VERSION 5.7 ;
  NOWIREEXTENSIONATPIN ON ;
  DIVIDERCHAR "/" ;
  BUSBITCHARS "[]" ;
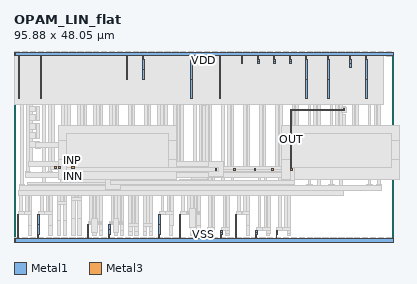
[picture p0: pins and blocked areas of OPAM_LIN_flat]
MACRO OPAM_LIN_flat
  CLASS BLOCK ;
  FOREIGN OPAM_LIN_flat ;
  ORIGIN 1.260 0.000 ;
  SIZE 95.880 BY 48.050 ;
  PIN VSS
    DIRECTION INOUT ;
    USE GROUND ;
    PORT
      LAYER Metal1 ;
        RECT -0.360 4.380 0.000 6.880 ;
        RECT 4.800 4.380 5.160 6.880 ;
        RECT 35.360 4.380 35.720 6.880 ;
        RECT 40.580 4.380 40.940 6.880 ;
        RECT 54.720 4.380 55.080 6.880 ;
        RECT -0.390 1.880 0.000 4.380 ;
        RECT 4.770 1.880 5.160 4.380 ;
        RECT 17.340 3.130 17.700 4.380 ;
        RECT 22.720 3.130 23.080 4.380 ;
        RECT 17.310 1.880 17.700 3.130 ;
        RECT 22.690 1.880 23.080 3.130 ;
        RECT 35.330 1.880 35.720 4.380 ;
        RECT 40.550 1.880 40.940 4.380 ;
        RECT 47.400 2.380 47.760 2.880 ;
        RECT 51.060 2.380 51.420 2.880 ;
        RECT 47.370 1.880 47.760 2.380 ;
        RECT 51.030 1.880 51.420 2.380 ;
        RECT 54.690 1.880 55.080 4.380 ;
        RECT 59.880 2.380 60.240 2.880 ;
        RECT 65.040 2.380 65.400 2.880 ;
        RECT 59.850 1.880 60.240 2.380 ;
        RECT 65.010 1.880 65.400 2.380 ;
        RECT -0.390 0.900 -0.160 1.880 ;
        RECT 4.770 0.900 5.000 1.880 ;
        RECT 17.310 0.900 17.540 1.880 ;
        RECT 22.690 0.900 22.920 1.880 ;
        RECT 35.330 0.900 35.560 1.880 ;
        RECT 40.550 0.900 40.780 1.880 ;
        RECT 47.370 0.900 47.600 1.880 ;
        RECT 51.030 0.900 51.260 1.880 ;
        RECT 54.690 0.900 54.920 1.880 ;
        RECT 59.850 0.900 60.080 1.880 ;
        RECT 65.010 0.900 65.240 1.880 ;
        RECT -1.000 0.000 94.620 0.900 ;
      LAYER Metal3 ;
        RECT -1.260 0.000 94.620 0.900 ;
    END
  END VSS
  PIN VDD
    DIRECTION INOUT ;
    USE POWER ;
    PORT
      LAYER Metal1 ;
        RECT -1.000 47.150 94.620 48.050 ;
        RECT -0.190 46.170 0.040 47.150 ;
        RECT 4.050 47.050 4.530 47.150 ;
        RECT 5.370 46.170 5.600 47.150 ;
        RECT 13.670 47.050 14.150 47.150 ;
        RECT 21.790 47.050 22.270 47.150 ;
        RECT 27.170 46.170 27.400 47.150 ;
        RECT 29.910 47.050 30.390 47.150 ;
        RECT 31.230 46.170 31.460 47.150 ;
        RECT 38.030 47.050 38.510 47.150 ;
        RECT 43.470 46.170 43.700 47.150 ;
        RECT 49.370 47.050 49.850 47.150 ;
        RECT 50.690 46.170 50.920 47.150 ;
        RECT 56.250 46.170 56.480 47.150 ;
        RECT 58.990 47.050 59.470 47.150 ;
        RECT 60.310 46.170 60.540 47.150 ;
        RECT 64.370 46.170 64.600 47.150 ;
        RECT 67.110 47.050 67.590 47.150 ;
        RECT 68.430 46.170 68.660 47.150 ;
        RECT 72.490 46.170 72.720 47.150 ;
        RECT 76.730 47.050 77.210 47.150 ;
        RECT 78.050 46.170 78.280 47.150 ;
        RECT 83.610 46.170 83.840 47.150 ;
        RECT 86.350 47.050 86.830 47.150 ;
        RECT 87.670 46.170 87.900 47.150 ;
        RECT -0.190 41.170 0.200 46.170 ;
        RECT 5.370 41.170 5.760 46.170 ;
        RECT 27.170 43.670 27.560 46.170 ;
        RECT 31.230 43.670 31.620 46.170 ;
        RECT 27.200 41.170 27.560 43.670 ;
        RECT 31.260 41.170 31.620 43.670 ;
        RECT 43.470 41.170 43.860 46.170 ;
        RECT 50.690 41.170 51.080 46.170 ;
        RECT 56.250 45.670 56.640 46.170 ;
        RECT 60.310 45.670 60.700 46.170 ;
        RECT 64.370 45.670 64.760 46.170 ;
        RECT 68.430 45.670 68.820 46.170 ;
        RECT 56.280 45.170 56.640 45.670 ;
        RECT 60.340 45.170 60.700 45.670 ;
        RECT 64.400 45.170 64.760 45.670 ;
        RECT 68.460 45.170 68.820 45.670 ;
        RECT 72.490 41.170 72.880 46.170 ;
        RECT 78.050 41.170 78.440 46.170 ;
        RECT 83.610 45.170 84.000 46.170 ;
        RECT 83.640 44.170 84.000 45.170 ;
        RECT 87.670 41.170 88.060 46.170 ;
        RECT -0.160 36.170 0.200 41.170 ;
        RECT 5.400 36.170 5.760 41.170 ;
        RECT 43.500 36.170 43.860 41.170 ;
        RECT 50.720 36.170 51.080 41.170 ;
        RECT 72.520 36.170 72.880 41.170 ;
        RECT 78.080 36.170 78.440 41.170 ;
        RECT 87.700 36.170 88.060 41.170 ;
      LAYER Metal3 ;
        RECT -1.260 47.150 94.620 48.050 ;
    END
  END VDD
  PIN INN
    DIRECTION INPUT ;
    ANTENNAGATEAREA 9.000000 ;
    PORT
      LAYER Metal3 ;
      RECT 13.520 16.180 13.950 16.720 ;
      RECT 14.640 16.180 15.050 16.720 ;
      RECT 15.750 16.180 16.160 16.720 ;
    END
  END INN
  PIN OUT
    DIRECTION INOUT ;
    ANTENNAGATEAREA 4.000000 ;
    ANTENNADIFFAREA 9.240000 ;
    PORT
      LAYER Metal3 ;
        RECT 81.990 33.590 82.390 33.640 ;
      RECT 68.725 33.290 82.390 33.590 ;
      RECT 68.725 18.560 69.025 33.290 ;
        RECT 81.990 33.240 82.390 33.290 ;
      RECT 49.675 18.160 50.075 18.560 ;
      RECT 54.375 18.000 54.800 18.560 ;
      RECT 59.440 18.000 59.875 18.560 ;
      RECT 63.875 18.000 64.320 18.560 ;
      RECT 68.675 18.160 69.075 18.560 ;
    END
  END OUT
  PIN INP
    DIRECTION INPUT ;
    ANTENNAGATEAREA 8.050000 ;
    PORT
      LAYER Metal3 ;
      RECT 9.040 18.560 9.490 19.220 ;
      RECT 9.990 18.560 10.560 19.220 ;
      RECT 13.290 18.560 13.920 19.220 ;
    END
  END INP
  OBS
      LAYER Via1 ;
        RECT 81.760 24.010 82.620 27.620 ;
        RECT 48.670 1.650 49.490 2.150 ;
        RECT 52.330 1.650 53.150 2.150 ;
        RECT 62.650 1.650 63.470 2.150 ;
        RECT 67.810 1.650 68.630 2.150 ;
        RECT 18.690 1.650 19.510 2.450 ;
        RECT 24.070 1.650 24.890 2.450 ;
        RECT 27.810 1.650 28.630 2.650 ;
        RECT 29.310 1.650 30.130 2.650 ;
        RECT 31.470 1.650 32.290 2.650 ;
        RECT 32.970 1.650 33.790 2.650 ;
        RECT 48.670 2.150 49.520 2.870 ;
        RECT 52.330 2.150 53.180 2.870 ;
        RECT 62.650 2.150 63.500 2.870 ;
        RECT 67.810 2.150 68.660 2.870 ;
        RECT 47.760 2.870 49.520 2.880 ;
        RECT 51.420 2.870 53.180 2.880 ;
        RECT 60.240 2.870 61.540 2.880 ;
        RECT 65.400 2.870 66.700 2.880 ;
        RECT 20.270 1.650 21.090 2.900 ;
        RECT 25.650 1.650 26.470 2.900 ;
        RECT 47.600 2.880 49.520 3.690 ;
        RECT 51.260 2.880 53.180 3.690 ;
        RECT 60.080 2.880 61.540 3.690 ;
        RECT 61.580 2.870 63.500 3.690 ;
        RECT 65.240 2.880 66.700 3.690 ;
        RECT 66.740 2.870 68.660 3.690 ;
        RECT 43.430 1.650 44.250 3.700 ;
        RECT 27.780 2.650 28.630 3.870 ;
        RECT 29.310 2.650 30.160 3.870 ;
        RECT 31.440 2.650 32.290 3.870 ;
        RECT 32.970 2.650 33.820 3.870 ;
        RECT 2.410 1.650 3.230 4.150 ;
        RECT 7.570 1.650 8.390 4.150 ;
        RECT 38.130 1.650 38.950 4.150 ;
        RECT 45.010 1.650 45.830 4.150 ;
        RECT 57.490 1.650 58.310 4.150 ;
        RECT 18.420 2.450 19.780 4.370 ;
        RECT 20.270 2.900 21.120 4.370 ;
        RECT 23.800 2.450 25.160 4.370 ;
        RECT 25.650 2.900 26.500 4.370 ;
        RECT 17.700 4.370 21.120 4.380 ;
        RECT 23.080 4.370 26.500 4.380 ;
        RECT 27.780 3.870 30.160 4.690 ;
        RECT 31.440 3.870 33.820 4.690 ;
        RECT 17.540 4.380 21.120 5.190 ;
        RECT 22.920 4.380 26.500 5.190 ;
        RECT 9.730 1.650 10.550 5.400 ;
        RECT 11.230 1.650 12.050 5.400 ;
        RECT 13.390 1.650 14.210 5.900 ;
        RECT 14.890 1.650 15.710 5.900 ;
        RECT 17.925 5.190 20.275 6.040 ;
        RECT 23.305 5.190 25.655 6.040 ;
        RECT 2.410 4.150 3.260 6.870 ;
        RECT 7.570 4.150 8.420 6.870 ;
        RECT 38.130 4.150 38.980 6.870 ;
        RECT 43.160 3.700 44.520 6.870 ;
        RECT 45.010 4.150 45.860 6.870 ;
        RECT 57.490 4.150 58.340 6.870 ;
        RECT 0.000 6.870 1.300 6.880 ;
        RECT 5.160 6.870 6.460 6.880 ;
        RECT 35.720 6.870 37.020 6.880 ;
        RECT 40.940 6.870 42.240 6.880 ;
        RECT 55.080 6.870 56.380 6.880 ;
        RECT -0.160 6.880 1.300 7.690 ;
        RECT 1.340 6.870 3.260 7.690 ;
        RECT 5.000 6.880 6.460 7.690 ;
        RECT 6.500 6.870 8.420 7.690 ;
        RECT 35.560 6.880 37.020 7.690 ;
        RECT 37.060 6.870 38.980 7.690 ;
        RECT 40.780 6.880 42.240 7.690 ;
        RECT 42.280 6.870 45.860 7.690 ;
        RECT 54.920 6.880 56.380 7.690 ;
        RECT 56.420 6.870 58.340 7.690 ;
        RECT 42.665 7.690 45.015 8.540 ;
        RECT 9.700 5.400 10.550 9.370 ;
        RECT 11.230 5.400 12.080 9.370 ;
        RECT 9.700 9.370 12.080 10.190 ;
        RECT 13.360 5.900 14.210 10.370 ;
        RECT 14.890 5.900 15.740 10.370 ;
        RECT 13.360 10.370 15.740 11.190 ;
        RECT 0.225 7.690 0.915 11.740 ;
        RECT 5.385 7.690 6.075 11.740 ;
        RECT 35.945 7.690 36.635 11.740 ;
        RECT 55.305 7.690 55.995 11.740 ;
        RECT 56.805 7.690 57.495 11.740 ;
        RECT 57.650 7.690 58.340 11.740 ;
        RECT -0.110 11.740 1.250 11.790 ;
        RECT 1.725 7.690 2.415 11.790 ;
        RECT 2.570 7.690 3.260 11.790 ;
        RECT 5.050 11.740 6.410 11.790 ;
        RECT 6.885 7.690 7.575 11.790 ;
        RECT 7.730 7.690 8.420 11.790 ;
        RECT 9.700 10.190 10.390 11.790 ;
        RECT 10.545 10.190 11.235 11.790 ;
        RECT 11.390 10.190 12.080 11.790 ;
        RECT 13.360 11.190 14.050 11.790 ;
        RECT 14.205 11.190 14.895 11.790 ;
        RECT 15.050 11.190 15.740 11.790 ;
        RECT 17.925 6.040 18.615 11.790 ;
        RECT 18.755 6.040 19.445 11.790 ;
        RECT 19.585 6.040 20.275 11.790 ;
        RECT 20.430 5.190 21.120 11.790 ;
        RECT 23.305 6.040 23.995 11.790 ;
        RECT 24.135 6.040 24.825 11.790 ;
        RECT 24.965 6.040 25.655 11.790 ;
        RECT 25.810 5.190 26.500 11.790 ;
        RECT 27.780 4.690 28.470 11.790 ;
        RECT 28.625 4.690 29.315 11.790 ;
        RECT 29.470 4.690 30.160 11.790 ;
        RECT 31.440 4.690 32.130 11.790 ;
        RECT 32.285 4.690 32.975 11.790 ;
        RECT 33.130 4.690 33.820 11.790 ;
        RECT 35.610 11.740 36.970 11.790 ;
        RECT 37.445 7.690 38.135 11.790 ;
        RECT 38.290 7.690 38.980 11.790 ;
        RECT 41.165 7.690 41.855 11.790 ;
        RECT 42.665 8.540 43.355 11.790 ;
        RECT 43.495 8.540 44.185 11.790 ;
        RECT 44.325 8.540 45.015 11.790 ;
        RECT 45.170 7.690 45.860 11.790 ;
        RECT 47.985 3.690 48.675 11.790 ;
        RECT 48.830 3.690 49.520 11.790 ;
        RECT 51.645 3.690 52.335 11.790 ;
        RECT 52.490 3.690 53.180 11.790 ;
        RECT 54.970 11.740 56.330 11.790 ;
        RECT 56.805 11.740 58.675 11.790 ;
        RECT 60.465 3.690 61.155 11.790 ;
        RECT 61.965 3.690 62.655 11.790 ;
        RECT 62.810 3.690 63.500 11.790 ;
        RECT 65.625 3.690 66.315 11.790 ;
        RECT 67.125 3.690 67.815 11.790 ;
        RECT 67.970 3.690 68.660 11.790 ;
        RECT 80.675 11.740 82.035 11.790 ;
        RECT -0.110 11.790 82.035 13.050 ;
        RECT -0.110 13.050 1.250 13.060 ;
        RECT 1.390 13.050 76.475 13.060 ;
        RECT -0.110 13.060 76.475 13.100 ;
        RECT 80.675 13.050 82.035 13.100 ;
        RECT 0.090 13.100 76.475 13.110 ;
        RECT 78.330 13.060 79.690 13.110 ;
        RECT 81.010 13.100 81.700 13.110 ;
        RECT 87.950 13.060 89.310 13.110 ;
        RECT 90.295 13.060 91.655 13.110 ;
        RECT 0.090 13.110 91.655 14.370 ;
        RECT 23.045 14.370 24.825 14.380 ;
        RECT 0.090 14.370 1.450 14.420 ;
        RECT 61.965 14.370 63.835 14.420 ;
        RECT 72.770 14.370 74.130 14.420 ;
        RECT 78.330 14.370 79.690 14.420 ;
        RECT 87.950 14.370 89.310 14.420 ;
        RECT 90.295 14.370 91.655 14.420 ;
        RECT 2.235 14.370 14.895 14.430 ;
        RECT 15.050 14.370 15.740 14.430 ;
        RECT 15.960 14.370 19.940 14.430 ;
        RECT 20.430 14.370 21.120 14.430 ;
        RECT 23.045 14.380 25.160 14.430 ;
        RECT 2.235 14.430 25.160 15.030 ;
        RECT 27.780 14.370 54.675 15.030 ;
        RECT 40.685 15.030 46.195 15.040 ;
        RECT 2.235 15.030 3.595 15.080 ;
        RECT 7.395 15.030 8.755 15.080 ;
        RECT 9.365 15.030 11.235 15.080 ;
        RECT 53.315 15.030 54.675 15.080 ;
        RECT 31.440 15.030 33.820 15.080 ;
        RECT 40.685 15.040 47.440 15.080 ;
        RECT 11.390 15.030 25.160 15.090 ;
        RECT 25.810 14.370 26.500 15.090 ;
        RECT 27.780 15.030 30.160 15.090 ;
        RECT 40.685 15.080 45.110 15.090 ;
        RECT 46.080 15.080 47.440 15.090 ;
        RECT 40.685 15.090 47.585 15.690 ;
        RECT 40.830 15.690 42.190 15.740 ;
        RECT 43.160 15.690 47.585 15.740 ;
        RECT 11.390 15.090 30.160 15.740 ;
        RECT 11.390 15.740 12.080 15.750 ;
        RECT 12.390 15.740 30.160 15.750 ;
        RECT 31.440 15.080 32.130 15.750 ;
        RECT 33.130 15.080 33.820 15.750 ;
        RECT 36.415 15.700 37.775 15.750 ;
        RECT 43.605 15.740 47.585 16.350 ;
        RECT 46.080 16.350 47.440 16.360 ;
        RECT 53.650 15.080 54.340 16.360 ;
        RECT 60.465 14.370 61.155 16.360 ;
        RECT 61.965 14.420 62.655 16.360 ;
        RECT 65.625 14.370 66.315 16.360 ;
        RECT 67.125 14.370 67.815 16.360 ;
        RECT 67.970 14.370 68.660 16.360 ;
        RECT 75.450 14.370 76.140 16.360 ;
        RECT 81.010 14.370 81.700 16.360 ;
        RECT 90.630 14.420 91.320 16.360 ;
        RECT 43.750 16.350 45.110 16.400 ;
        RECT 45.250 16.360 47.440 16.400 ;
        RECT 1.590 16.360 2.950 16.410 ;
        RECT 5.985 15.030 6.675 16.410 ;
        RECT 7.150 16.360 8.510 16.410 ;
        RECT 10.545 15.080 11.235 16.410 ;
        RECT 11.390 15.750 37.775 16.410 ;
        RECT 38.290 15.030 38.980 16.410 ;
        RECT 44.085 16.400 44.775 16.410 ;
        RECT 45.250 16.400 47.105 16.410 ;
        RECT 47.985 15.030 48.675 16.410 ;
        RECT 48.830 15.030 49.520 16.410 ;
        RECT 51.305 15.030 51.995 16.410 ;
        RECT 52.470 16.360 54.340 16.410 ;
        RECT 60.130 16.360 61.490 16.410 ;
        RECT 61.630 16.360 62.990 16.410 ;
        RECT 65.290 16.360 66.650 16.410 ;
        RECT 66.790 16.360 68.995 16.410 ;
        RECT 73.105 14.420 73.795 16.410 ;
        RECT 74.270 16.360 76.140 16.410 ;
        RECT 78.665 14.420 79.355 16.410 ;
        RECT 79.830 16.360 81.700 16.410 ;
        RECT 83.890 16.360 86.095 16.410 ;
        RECT 88.285 14.420 88.975 16.410 ;
        RECT 89.450 16.360 91.320 16.410 ;
        RECT 1.590 16.410 91.320 17.670 ;
        RECT 10.545 17.670 11.235 17.680 ;
        RECT 11.390 17.670 13.125 17.680 ;
        RECT 23.390 17.670 70.070 17.680 ;
        RECT 1.590 17.670 2.950 17.720 ;
        RECT 7.150 17.670 8.510 17.720 ;
        RECT 18.820 17.670 20.690 17.720 ;
        RECT 74.270 17.670 76.140 17.720 ;
        RECT 79.830 17.670 81.700 17.720 ;
        RECT 83.890 17.670 86.095 17.720 ;
        RECT 89.450 17.670 91.320 17.720 ;
        RECT 10.545 17.680 13.125 17.730 ;
        RECT 15.605 17.670 16.295 17.730 ;
        RECT 16.450 17.670 17.140 17.730 ;
        RECT 18.820 17.720 19.510 17.730 ;
        RECT 19.665 17.720 20.355 17.730 ;
        RECT 22.545 17.680 70.915 17.730 ;
        RECT 10.545 17.730 70.915 18.330 ;
        RECT 47.985 18.330 70.915 18.340 ;
        RECT 8.600 18.330 34.155 18.380 ;
        RECT 38.290 18.330 40.145 18.380 ;
        RECT 7.485 17.720 8.175 18.390 ;
        RECT 8.600 18.380 33.715 18.390 ;
        RECT 36.750 18.330 37.440 18.390 ;
        RECT 38.290 18.380 38.980 18.390 ;
        RECT 39.120 18.380 39.810 18.390 ;
        RECT 40.475 18.340 41.835 18.390 ;
        RECT 44.085 18.330 44.775 18.390 ;
        RECT 45.585 18.330 46.275 18.390 ;
        RECT 46.415 18.330 47.105 18.390 ;
        RECT 47.650 18.340 70.915 18.390 ;
        RECT 7.485 18.390 70.915 18.990 ;
        RECT 1.925 17.720 2.615 19.000 ;
        RECT 7.485 18.990 14.880 19.000 ;
        RECT 15.605 18.990 16.295 19.000 ;
        RECT 19.665 18.990 20.355 19.000 ;
        RECT 22.545 18.990 24.415 19.040 ;
        RECT 56.865 18.990 58.735 19.040 ;
        RECT 60.925 18.990 62.795 19.040 ;
        RECT 64.985 18.990 66.855 19.040 ;
        RECT 68.185 18.990 70.915 19.040 ;
        RECT 25.475 18.990 50.565 19.040 ;
        RECT 1.925 19.000 3.795 19.050 ;
        RECT 5.985 17.670 6.675 19.050 ;
        RECT 7.485 19.000 16.295 19.050 ;
        RECT 19.665 19.000 21.535 19.050 ;
        RECT 22.880 19.040 23.570 19.050 ;
        RECT 23.725 19.040 24.415 19.050 ;
        RECT 24.570 18.990 25.260 19.050 ;
        RECT 25.475 19.040 49.115 19.050 ;
        RECT 49.185 19.040 50.565 19.050 ;
        RECT 53.650 18.990 55.265 19.050 ;
        RECT 58.985 18.990 60.365 19.050 ;
        RECT 63.385 18.990 64.765 19.050 ;
        RECT 68.185 19.040 69.735 19.050 ;
        RECT 1.925 19.050 16.295 20.310 ;
        RECT 19.665 19.050 49.115 20.310 ;
        RECT 1.925 20.310 3.795 20.360 ;
        RECT 7.485 20.310 9.355 20.360 ;
        RECT 10.365 20.310 12.235 20.360 ;
        RECT 14.425 20.310 16.295 20.360 ;
        RECT 19.665 20.310 21.535 20.360 ;
        RECT 27.450 20.310 30.495 20.360 ;
        RECT 31.510 20.310 33.380 20.360 ;
        RECT 34.725 20.310 37.440 20.360 ;
        RECT 37.955 20.310 41.500 20.360 ;
        RECT 46.415 20.310 49.115 20.360 ;
        RECT 2.770 20.360 3.460 24.010 ;
        RECT 4.130 23.750 5.510 24.010 ;
        RECT 2.770 24.010 5.510 25.130 ;
        RECT 2.770 25.130 4.160 25.370 ;
        RECT 4.390 25.130 5.250 25.370 ;
        RECT 2.770 25.370 3.460 26.260 ;
        RECT 2.770 26.260 4.160 27.620 ;
        RECT 2.770 27.620 3.460 28.510 ;
        RECT 2.770 28.510 4.160 29.870 ;
        RECT 2.770 29.870 3.460 30.760 ;
        RECT 2.770 30.760 4.160 32.120 ;
        RECT 81.010 17.720 81.700 32.750 ;
        RECT 2.770 32.120 3.460 33.010 ;
        RECT 81.010 32.750 82.880 34.130 ;
        RECT 2.770 33.010 4.160 34.370 ;
        RECT 81.760 34.130 82.620 34.370 ;
        RECT 45.585 20.310 46.275 34.510 ;
        RECT 46.415 20.360 47.105 34.510 ;
        RECT 47.245 20.360 47.935 34.510 ;
        RECT 0.425 14.420 1.115 35.360 ;
        RECT 1.925 20.360 2.615 35.360 ;
        RECT 2.770 34.370 3.460 35.360 ;
        RECT 5.985 20.310 6.675 35.360 ;
        RECT 7.485 20.360 8.175 35.360 ;
        RECT 8.330 20.360 9.020 35.360 ;
        RECT 18.820 18.990 19.510 35.360 ;
        RECT 19.665 20.360 20.355 35.360 ;
        RECT 20.510 20.360 21.200 35.360 ;
        RECT 22.880 20.310 23.570 35.360 ;
        RECT 23.725 20.310 24.415 35.360 ;
        RECT 24.570 20.310 25.260 35.360 ;
        RECT 44.085 20.310 44.775 35.360 ;
        RECT 45.585 34.510 47.935 35.360 ;
        RECT 48.090 20.360 48.780 35.360 ;
        RECT 51.305 18.990 51.995 35.360 ;
        RECT 52.805 18.990 53.495 35.360 ;
        RECT 53.650 19.050 54.340 35.360 ;
        RECT 73.105 17.670 73.795 35.360 ;
        RECT 74.605 17.720 75.295 35.360 ;
        RECT 75.450 17.720 76.140 35.360 ;
        RECT 78.665 17.670 79.355 35.360 ;
        RECT 80.165 17.720 80.855 35.360 ;
        RECT 81.010 34.130 81.700 35.360 ;
        RECT 88.285 17.670 88.975 35.360 ;
        RECT 89.785 17.720 90.475 35.360 ;
        RECT 90.630 17.720 91.320 35.360 ;
        RECT 0.040 35.360 1.500 36.170 ;
        RECT 5.600 35.360 7.060 36.170 ;
        RECT 43.700 35.360 45.160 36.170 ;
        RECT 50.920 35.360 52.380 36.170 ;
        RECT 72.720 35.360 74.180 36.170 ;
        RECT 78.280 35.360 79.740 36.170 ;
        RECT 87.900 35.360 89.360 36.170 ;
        RECT 0.200 36.170 1.500 36.180 ;
        RECT 1.540 35.360 3.460 36.180 ;
        RECT 5.760 36.170 7.060 36.180 ;
        RECT 7.100 35.360 9.020 36.180 ;
        RECT 43.860 36.170 45.160 36.180 ;
        RECT 45.200 35.360 48.780 36.180 ;
        RECT 51.080 36.170 52.380 36.180 ;
        RECT 52.420 35.360 54.340 36.180 ;
        RECT 72.880 36.170 74.180 36.180 ;
        RECT 74.220 35.360 76.140 36.180 ;
        RECT 78.440 36.170 79.740 36.180 ;
        RECT 79.780 35.360 81.700 36.180 ;
        RECT 88.060 36.170 89.360 36.180 ;
        RECT 89.400 35.360 91.320 36.180 ;
        RECT 18.820 35.360 21.200 36.180 ;
        RECT 22.880 35.360 25.260 36.180 ;
        RECT 27.785 20.360 28.475 40.360 ;
        RECT 28.630 20.360 29.320 40.360 ;
        RECT 31.845 20.360 32.535 40.360 ;
        RECT 32.690 20.360 33.380 40.360 ;
        RECT 27.400 40.360 29.320 41.170 ;
        RECT 31.460 40.360 33.380 41.170 ;
        RECT 27.560 41.170 29.320 41.180 ;
        RECT 31.620 41.170 33.380 41.180 ;
        RECT 35.060 20.360 35.750 41.360 ;
        RECT 35.905 20.360 36.595 41.360 ;
        RECT 36.750 20.360 37.440 41.360 ;
        RECT 39.120 20.360 39.810 41.360 ;
        RECT 39.965 20.360 40.655 41.360 ;
        RECT 40.810 20.360 41.500 41.360 ;
        RECT 2.610 36.180 3.460 41.400 ;
        RECT 8.170 36.180 9.020 41.400 ;
        RECT 18.820 36.180 19.670 41.400 ;
        RECT 20.350 36.180 21.200 41.400 ;
        RECT 22.880 36.180 23.730 41.400 ;
        RECT 24.410 36.180 25.260 41.400 ;
        RECT 47.930 36.180 48.780 41.400 ;
        RECT 53.490 36.180 54.340 41.400 ;
        RECT 75.290 36.180 76.140 41.400 ;
        RECT 80.850 36.180 81.700 41.400 ;
        RECT 90.470 36.180 91.320 41.400 ;
        RECT 46.080 36.180 47.440 41.850 ;
        RECT 35.060 41.360 37.440 42.180 ;
        RECT 39.120 41.360 41.500 42.180 ;
        RECT 84.225 17.720 84.915 43.360 ;
        RECT 85.070 17.720 85.760 43.360 ;
        RECT 28.470 41.180 29.320 43.900 ;
        RECT 32.530 41.180 33.380 43.900 ;
        RECT 83.840 43.360 85.760 44.170 ;
        RECT 84.000 44.170 85.760 44.180 ;
        RECT 56.865 19.040 57.555 44.360 ;
        RECT 57.710 19.040 58.400 44.360 ;
        RECT 60.925 19.040 61.615 44.360 ;
        RECT 61.770 19.040 62.460 44.360 ;
        RECT 64.985 19.040 65.675 44.360 ;
        RECT 65.830 19.040 66.520 44.360 ;
        RECT 69.045 19.050 69.735 44.360 ;
        RECT 69.890 19.040 70.580 44.360 ;
        RECT 35.060 42.180 35.910 44.400 ;
        RECT 36.590 42.180 37.440 44.400 ;
        RECT 39.120 42.180 39.970 44.400 ;
        RECT 40.650 42.180 41.500 44.400 ;
        RECT 10.700 20.360 11.390 44.810 ;
        RECT 11.545 20.360 12.235 44.810 ;
        RECT 12.390 20.310 13.080 44.810 ;
        RECT 14.760 20.360 15.450 44.860 ;
        RECT 15.605 20.360 16.295 44.860 ;
        RECT 16.450 18.990 17.140 44.860 ;
        RECT 56.480 44.360 58.400 45.170 ;
        RECT 60.540 44.360 62.460 45.170 ;
        RECT 64.600 44.360 66.520 45.170 ;
        RECT 68.660 44.360 70.580 45.170 ;
        RECT 56.640 45.170 58.400 45.180 ;
        RECT 60.700 45.170 62.460 45.180 ;
        RECT 64.760 45.170 66.520 45.180 ;
        RECT 68.820 45.170 70.580 45.180 ;
        RECT 84.910 44.180 85.760 45.400 ;
        RECT 10.700 44.810 13.080 45.630 ;
        RECT 14.760 44.860 17.140 45.680 ;
        RECT 57.550 45.180 58.400 45.900 ;
        RECT 61.610 45.180 62.460 45.900 ;
        RECT 65.670 45.180 66.520 45.900 ;
        RECT 69.730 45.180 70.580 45.900 ;
        RECT 10.700 45.630 11.550 46.125 ;
        RECT 12.230 45.630 13.080 46.125 ;
        RECT 14.760 45.680 15.610 46.150 ;
        RECT 16.290 45.680 17.140 46.150 ;
        RECT 2.610 41.400 3.430 46.400 ;
        RECT 8.170 41.400 8.990 46.400 ;
        RECT 10.730 46.125 11.550 46.400 ;
        RECT 12.230 46.125 13.050 46.400 ;
        RECT 14.790 46.150 15.610 46.400 ;
        RECT 16.290 46.150 17.110 46.400 ;
        RECT 18.850 41.400 19.670 46.400 ;
        RECT 20.350 41.400 21.170 46.400 ;
        RECT 22.910 41.400 23.730 46.400 ;
        RECT 24.410 41.400 25.230 46.400 ;
        RECT 28.470 43.900 29.290 46.400 ;
        RECT 32.530 43.900 33.350 46.400 ;
        RECT 35.090 44.400 35.910 46.400 ;
        RECT 36.590 44.400 37.410 46.400 ;
        RECT 39.150 44.400 39.970 46.400 ;
        RECT 40.650 44.400 41.470 46.400 ;
        RECT 46.350 41.850 47.170 46.400 ;
        RECT 47.930 41.400 48.750 46.400 ;
        RECT 53.490 41.400 54.310 46.400 ;
        RECT 57.550 45.900 58.370 46.400 ;
        RECT 61.610 45.900 62.430 46.400 ;
        RECT 65.670 45.900 66.490 46.400 ;
        RECT 69.730 45.900 70.550 46.400 ;
        RECT 75.290 41.400 76.110 46.400 ;
        RECT 80.850 41.400 81.670 46.400 ;
        RECT 84.910 45.400 85.730 46.400 ;
        RECT 90.470 41.400 91.290 46.400 ;
        RECT 81.760 28.510 82.620 32.120 ;
        RECT 46.850 46.910 48.230 48.290 ;
        RECT 48.850 46.910 50.230 48.290 ;
        RECT 50.850 46.910 52.230 48.290 ;
        RECT 52.850 46.910 54.230 48.290 ;
        RECT 54.850 46.910 56.230 48.290 ;
        RECT 56.850 46.910 58.230 48.290 ;
        RECT 58.850 46.910 60.230 48.290 ;
        RECT 60.850 46.910 62.230 48.290 ;
        RECT 62.850 46.910 64.230 48.290 ;
        RECT 64.850 46.910 66.230 48.290 ;
        RECT 66.850 46.910 68.230 48.290 ;
        RECT 68.850 46.910 70.230 48.290 ;
        RECT 70.850 46.910 72.230 48.290 ;
        RECT 72.850 46.910 74.230 48.290 ;
        RECT 74.850 46.910 76.230 48.290 ;
        RECT 76.850 46.910 78.230 48.290 ;
        RECT 78.850 46.910 80.230 48.290 ;
        RECT 80.850 46.910 82.230 48.290 ;
        RECT 82.850 46.910 84.230 48.290 ;
        RECT 84.850 46.910 86.230 48.290 ;
        RECT 86.850 46.910 88.230 48.290 ;
        RECT 88.850 46.910 90.230 48.290 ;
        RECT 90.850 46.910 92.230 48.290 ;
        RECT 92.850 46.910 94.230 48.290 ;
        RECT 42.850 46.910 44.230 48.290 ;
        RECT 44.850 46.910 46.230 48.290 ;
        RECT 4.390 30.760 5.250 34.370 ;
        RECT 4.390 26.260 5.250 29.870 ;
        RECT -1.150 46.910 0.230 48.290 ;
        RECT 0.850 46.910 2.230 48.290 ;
        RECT 2.850 46.910 4.230 48.290 ;
        RECT 4.850 46.910 6.230 48.290 ;
        RECT 6.850 46.910 8.230 48.290 ;
        RECT 8.850 46.910 10.230 48.290 ;
        RECT 10.850 46.910 12.230 48.290 ;
        RECT 12.850 46.910 14.230 48.290 ;
        RECT 14.850 46.910 16.230 48.290 ;
        RECT 16.850 46.910 18.230 48.290 ;
        RECT 18.850 46.910 20.230 48.290 ;
        RECT 20.850 46.910 22.230 48.290 ;
        RECT 22.850 46.910 24.230 48.290 ;
        RECT 24.850 46.910 26.230 48.290 ;
        RECT 26.850 46.910 28.230 48.290 ;
        RECT 28.850 46.910 30.230 48.290 ;
        RECT 30.850 46.910 32.230 48.290 ;
        RECT 32.850 46.910 34.230 48.290 ;
        RECT 34.850 46.910 36.230 48.290 ;
        RECT 36.850 46.910 38.230 48.290 ;
        RECT 38.850 46.910 40.230 48.290 ;
        RECT 40.850 46.910 42.230 48.290 ;
        RECT 8.850 -0.240 10.230 1.140 ;
        RECT 10.850 -0.240 12.230 1.140 ;
        RECT 12.850 -0.240 14.230 1.140 ;
        RECT 14.850 -0.240 16.230 1.140 ;
        RECT 16.850 -0.240 18.230 1.140 ;
        RECT 18.850 -0.240 20.230 1.140 ;
        RECT 20.850 -0.240 22.230 1.140 ;
        RECT 22.850 -0.240 24.230 1.140 ;
        RECT 24.850 -0.240 26.230 1.140 ;
        RECT 26.850 -0.240 28.230 1.140 ;
        RECT 28.850 -0.240 30.230 1.140 ;
        RECT 30.850 -0.240 32.230 1.140 ;
        RECT 32.850 -0.240 34.230 1.140 ;
        RECT 34.850 -0.240 36.230 1.140 ;
        RECT 36.850 -0.240 38.230 1.140 ;
        RECT 38.850 -0.240 40.230 1.140 ;
        RECT 40.850 -0.240 42.230 1.140 ;
        RECT 42.850 -0.240 44.230 1.140 ;
        RECT 44.850 -0.240 46.230 1.140 ;
        RECT -1.150 -0.240 0.230 1.140 ;
        RECT 0.850 -0.240 2.230 1.140 ;
        RECT 2.850 -0.240 4.230 1.140 ;
        RECT 4.850 -0.240 6.230 1.140 ;
        RECT 6.850 -0.240 8.230 1.140 ;
        RECT 56.850 -0.240 58.230 1.140 ;
        RECT 58.850 -0.240 60.230 1.140 ;
        RECT 60.850 -0.240 62.230 1.140 ;
        RECT 62.850 -0.240 64.230 1.140 ;
        RECT 64.850 -0.240 66.230 1.140 ;
        RECT 66.850 -0.240 68.230 1.140 ;
        RECT 68.850 -0.240 70.230 1.140 ;
        RECT 70.850 -0.240 72.230 1.140 ;
        RECT 72.850 -0.240 74.230 1.140 ;
        RECT 74.850 -0.240 76.230 1.140 ;
        RECT 76.850 -0.240 78.230 1.140 ;
        RECT 78.850 -0.240 80.230 1.140 ;
        RECT 80.850 -0.240 82.230 1.140 ;
        RECT 82.850 -0.240 84.230 1.140 ;
        RECT 84.850 -0.240 86.230 1.140 ;
        RECT 86.850 -0.240 88.230 1.140 ;
        RECT 88.850 -0.240 90.230 1.140 ;
        RECT 90.850 -0.240 92.230 1.140 ;
        RECT 92.850 -0.240 94.230 1.140 ;
        RECT 46.850 -0.240 48.230 1.140 ;
        RECT 48.850 -0.240 50.230 1.140 ;
        RECT 50.850 -0.240 52.230 1.140 ;
        RECT 52.850 -0.240 54.230 1.140 ;
        RECT 54.850 -0.240 56.230 1.140 ;
      LAYER Via2 ;
        RECT -0.110 11.740 1.250 11.790 ;
        RECT 5.050 11.740 6.410 11.790 ;
        RECT 35.610 11.740 36.970 11.790 ;
        RECT 54.970 11.740 56.330 11.790 ;
        RECT 57.315 11.740 58.675 11.790 ;
        RECT 80.675 11.740 82.035 11.790 ;
        RECT -0.110 11.790 82.035 13.050 ;
        RECT -0.110 13.050 1.250 13.060 ;
        RECT 1.390 13.050 76.475 13.060 ;
        RECT -0.110 13.060 76.475 13.100 ;
        RECT 80.675 13.050 82.035 13.100 ;
        RECT 0.090 13.100 76.475 13.110 ;
        RECT 78.330 13.060 79.690 13.110 ;
        RECT 87.950 13.060 89.310 13.110 ;
        RECT 90.295 13.060 91.655 13.110 ;
        RECT 0.090 13.110 91.655 14.370 ;
        RECT 23.045 14.370 24.425 14.380 ;
        RECT 0.090 14.370 1.450 14.420 ;
        RECT 62.475 14.370 63.835 14.420 ;
        RECT 72.770 14.370 74.130 14.420 ;
        RECT 78.330 14.370 79.690 14.420 ;
        RECT 87.950 14.370 89.310 14.420 ;
        RECT 90.295 14.370 91.655 14.420 ;
        RECT 2.235 14.370 14.385 14.430 ;
        RECT 15.960 14.370 19.940 14.430 ;
        RECT 23.045 14.380 25.160 14.430 ;
        RECT 2.235 14.430 25.160 15.030 ;
        RECT 28.290 14.370 54.675 15.030 ;
        RECT 28.290 15.030 29.650 15.040 ;
        RECT 40.685 15.030 46.195 15.040 ;
        RECT 2.235 15.030 3.595 15.080 ;
        RECT 7.395 15.030 8.755 15.080 ;
        RECT 9.365 15.030 10.725 15.080 ;
        RECT 28.290 15.040 29.655 15.080 ;
        RECT 31.950 15.030 33.310 15.080 ;
        RECT 53.315 15.030 54.675 15.080 ;
        RECT 40.685 15.040 47.440 15.080 ;
        RECT 12.055 15.030 25.160 15.090 ;
        RECT 28.295 15.080 29.655 15.090 ;
        RECT 40.685 15.080 45.110 15.090 ;
        RECT 46.080 15.080 47.440 15.090 ;
        RECT 40.685 15.090 47.585 15.690 ;
        RECT 12.055 15.090 29.655 15.740 ;
        RECT 40.830 15.690 42.190 15.740 ;
        RECT 43.160 15.690 47.585 15.740 ;
        RECT 13.060 15.740 29.655 15.750 ;
        RECT 36.415 15.700 37.775 15.750 ;
        RECT 43.605 15.740 47.585 16.350 ;
        RECT 46.080 16.350 47.440 16.360 ;
        RECT 43.750 16.350 45.110 16.400 ;
        RECT 45.250 16.360 47.440 16.400 ;
        RECT 1.590 16.360 2.950 16.410 ;
        RECT 7.150 16.360 8.510 16.410 ;
        RECT 11.760 15.750 37.775 16.410 ;
        RECT 45.250 16.400 46.610 16.410 ;
        RECT 52.470 16.360 53.830 16.410 ;
        RECT 60.130 16.360 61.490 16.410 ;
        RECT 61.630 16.360 62.990 16.410 ;
        RECT 65.290 16.360 66.650 16.410 ;
        RECT 66.790 16.360 68.995 16.410 ;
        RECT 74.270 16.360 75.630 16.410 ;
        RECT 79.830 16.360 81.190 16.410 ;
        RECT 83.890 16.360 86.095 16.410 ;
        RECT 89.450 16.360 90.810 16.410 ;
        RECT 1.590 16.410 90.810 17.670 ;
        RECT 11.745 17.670 13.125 17.680 ;
        RECT 23.390 17.670 70.070 17.680 ;
        RECT 1.590 17.670 2.950 17.720 ;
        RECT 7.150 17.670 8.510 17.720 ;
        RECT 19.330 17.670 20.690 17.720 ;
        RECT 74.270 17.670 75.630 17.720 ;
        RECT 79.830 17.670 81.190 17.720 ;
        RECT 83.890 17.670 86.095 17.720 ;
        RECT 89.450 17.670 90.810 17.720 ;
        RECT 22.545 17.680 70.915 17.720 ;
        RECT 11.055 17.680 13.125 17.730 ;
        RECT 22.545 17.720 23.905 17.730 ;
        RECT 24.235 17.720 70.915 17.730 ;
        RECT 11.055 17.730 70.915 18.330 ;
        RECT 8.600 18.330 10.880 18.340 ;
        RECT 11.055 18.330 34.155 18.340 ;
        RECT 48.495 18.330 70.915 18.340 ;
        RECT 8.600 18.340 34.155 18.380 ;
        RECT 38.785 18.330 40.145 18.380 ;
        RECT 8.600 18.380 33.715 18.390 ;
        RECT 40.475 18.340 41.835 18.390 ;
        RECT 47.650 18.340 70.915 18.390 ;
        RECT 7.900 18.390 70.915 18.990 ;
        RECT 7.900 18.990 14.880 19.000 ;
        RECT 22.545 18.990 23.905 19.040 ;
        RECT 57.375 18.990 58.735 19.040 ;
        RECT 61.435 18.990 62.795 19.040 ;
        RECT 65.495 18.990 66.855 19.040 ;
        RECT 68.185 18.990 70.915 19.040 ;
        RECT 24.975 18.990 50.565 19.040 ;
        RECT 2.435 19.000 3.795 19.050 ;
        RECT 7.900 19.000 15.785 19.050 ;
        RECT 20.175 19.000 21.535 19.050 ;
        RECT 24.975 19.040 49.115 19.050 ;
        RECT 49.185 19.040 50.565 19.050 ;
        RECT 53.885 18.990 55.265 19.050 ;
        RECT 58.985 18.990 60.365 19.050 ;
        RECT 63.385 18.990 64.765 19.050 ;
        RECT 68.185 19.040 69.565 19.050 ;
        RECT 2.435 19.050 15.785 20.310 ;
        RECT 20.175 19.050 49.115 20.310 ;
        RECT 2.435 20.310 3.795 20.360 ;
        RECT 7.995 20.310 9.355 20.360 ;
        RECT 10.365 20.310 11.725 20.360 ;
        RECT 14.425 20.310 15.785 20.360 ;
        RECT 20.175 20.310 21.535 20.360 ;
        RECT 27.450 20.310 28.810 20.360 ;
        RECT 29.135 20.310 30.495 20.360 ;
        RECT 31.510 20.310 32.870 20.360 ;
        RECT 34.725 20.310 36.930 20.360 ;
        RECT 37.955 20.310 39.315 20.360 ;
        RECT 39.630 20.310 40.990 20.360 ;
        RECT 46.910 20.310 49.115 20.360 ;
        RECT 4.130 23.750 5.510 23.800 ;
        RECT 24.975 20.310 26.255 23.800 ;
        RECT 4.130 23.800 26.255 25.080 ;
        RECT 4.130 25.080 5.510 25.130 ;
        RECT 46.080 34.510 47.440 41.850 ;
        RECT 81.500 32.750 82.880 34.130 ;
        RECT 46.850 46.910 48.230 48.290 ;
        RECT 48.850 46.910 50.230 48.290 ;
        RECT 50.850 46.910 52.230 48.290 ;
        RECT 52.850 46.910 54.230 48.290 ;
        RECT 54.850 46.910 56.230 48.290 ;
        RECT 56.850 46.910 58.230 48.290 ;
        RECT 58.850 46.910 60.230 48.290 ;
        RECT 60.850 46.910 62.230 48.290 ;
        RECT 62.850 46.910 64.230 48.290 ;
        RECT 64.850 46.910 66.230 48.290 ;
        RECT 66.850 46.910 68.230 48.290 ;
        RECT 68.850 46.910 70.230 48.290 ;
        RECT 70.850 46.910 72.230 48.290 ;
        RECT 72.850 46.910 74.230 48.290 ;
        RECT 74.850 46.910 76.230 48.290 ;
        RECT 76.850 46.910 78.230 48.290 ;
        RECT 78.850 46.910 80.230 48.290 ;
        RECT 80.850 46.910 82.230 48.290 ;
        RECT 82.850 46.910 84.230 48.290 ;
        RECT 84.850 46.910 86.230 48.290 ;
        RECT 86.850 46.910 88.230 48.290 ;
        RECT 88.850 46.910 90.230 48.290 ;
        RECT 90.850 46.910 92.230 48.290 ;
        RECT 92.850 46.910 94.230 48.290 ;
        RECT -1.150 46.910 0.230 48.290 ;
        RECT 0.850 46.910 2.230 48.290 ;
        RECT 2.850 46.910 4.230 48.290 ;
        RECT 4.850 46.910 6.230 48.290 ;
        RECT 6.850 46.910 8.230 48.290 ;
        RECT 8.850 46.910 10.230 48.290 ;
        RECT 10.850 46.910 12.230 48.290 ;
        RECT 12.850 46.910 14.230 48.290 ;
        RECT 14.850 46.910 16.230 48.290 ;
        RECT 16.850 46.910 18.230 48.290 ;
        RECT 18.850 46.910 20.230 48.290 ;
        RECT 20.850 46.910 22.230 48.290 ;
        RECT 22.850 46.910 24.230 48.290 ;
        RECT 24.850 46.910 26.230 48.290 ;
        RECT 26.850 46.910 28.230 48.290 ;
        RECT 28.850 46.910 30.230 48.290 ;
        RECT 30.850 46.910 32.230 48.290 ;
        RECT 32.850 46.910 34.230 48.290 ;
        RECT 34.850 46.910 36.230 48.290 ;
        RECT 36.850 46.910 38.230 48.290 ;
        RECT 38.850 46.910 40.230 48.290 ;
        RECT 40.850 46.910 42.230 48.290 ;
        RECT 42.850 46.910 44.230 48.290 ;
        RECT 44.850 46.910 46.230 48.290 ;
        RECT 18.420 2.450 19.780 6.040 ;
        RECT 23.800 2.450 25.160 6.040 ;
        RECT 43.160 3.700 44.520 8.540 ;
        RECT -1.150 -0.240 0.230 1.140 ;
        RECT 0.850 -0.240 2.230 1.140 ;
        RECT 2.850 -0.240 4.230 1.140 ;
        RECT 4.850 -0.240 6.230 1.140 ;
        RECT 6.850 -0.240 8.230 1.140 ;
        RECT 8.850 -0.240 10.230 1.140 ;
        RECT 10.850 -0.240 12.230 1.140 ;
        RECT 12.850 -0.240 14.230 1.140 ;
        RECT 14.850 -0.240 16.230 1.140 ;
        RECT 16.850 -0.240 18.230 1.140 ;
        RECT 18.850 -0.240 20.230 1.140 ;
        RECT 20.850 -0.240 22.230 1.140 ;
        RECT 22.850 -0.240 24.230 1.140 ;
        RECT 24.850 -0.240 26.230 1.140 ;
        RECT 26.850 -0.240 28.230 1.140 ;
        RECT 28.850 -0.240 30.230 1.140 ;
        RECT 30.850 -0.240 32.230 1.140 ;
        RECT 32.850 -0.240 34.230 1.140 ;
        RECT 34.850 -0.240 36.230 1.140 ;
        RECT 36.850 -0.240 38.230 1.140 ;
        RECT 38.850 -0.240 40.230 1.140 ;
        RECT 40.850 -0.240 42.230 1.140 ;
        RECT 42.850 -0.240 44.230 1.140 ;
        RECT 44.850 -0.240 46.230 1.140 ;
        RECT 58.850 -0.240 60.230 1.140 ;
        RECT 60.850 -0.240 62.230 1.140 ;
        RECT 62.850 -0.240 64.230 1.140 ;
        RECT 64.850 -0.240 66.230 1.140 ;
        RECT 66.850 -0.240 68.230 1.140 ;
        RECT 68.850 -0.240 70.230 1.140 ;
        RECT 70.850 -0.240 72.230 1.140 ;
        RECT 72.850 -0.240 74.230 1.140 ;
        RECT 74.850 -0.240 76.230 1.140 ;
        RECT 76.850 -0.240 78.230 1.140 ;
        RECT 78.850 -0.240 80.230 1.140 ;
        RECT 80.850 -0.240 82.230 1.140 ;
        RECT 82.850 -0.240 84.230 1.140 ;
        RECT 84.850 -0.240 86.230 1.140 ;
        RECT 86.850 -0.240 88.230 1.140 ;
        RECT 88.850 -0.240 90.230 1.140 ;
        RECT 90.850 -0.240 92.230 1.140 ;
        RECT 92.850 -0.240 94.230 1.140 ;
        RECT 46.850 -0.240 48.230 1.140 ;
        RECT 48.850 -0.240 50.230 1.140 ;
        RECT 50.850 -0.240 52.230 1.140 ;
        RECT 52.850 -0.240 54.230 1.140 ;
        RECT 54.850 -0.240 56.230 1.140 ;
        RECT 56.850 -0.240 58.230 1.140 ;
      LAYER Via3 ;
        RECT 47.985 16.470 51.765 20.250 ;
        RECT 21.845 13.170 25.625 15.870 ;
        RECT 9.945 15.870 39.725 20.950 ;
        RECT 4.130 23.750 5.510 23.800 ;
        RECT 9.945 20.950 14.125 23.800 ;
        RECT 24.975 20.950 26.255 23.800 ;
        RECT 4.130 23.800 26.255 25.080 ;
        RECT 4.130 25.080 5.510 25.130 ;
        RECT 9.945 25.080 14.125 25.570 ;
        RECT 35.745 20.950 39.725 25.570 ;
        RECT 9.945 25.570 39.725 29.550 ;
        RECT 66.385 15.870 96.165 20.950 ;
        RECT 66.385 20.950 70.565 25.570 ;
        RECT 92.185 20.950 96.165 25.570 ;
        RECT 66.385 25.570 96.165 29.550 ;
      LAYER Via4 ;
        RECT 21.845 13.170 25.625 14.460 ;
        RECT 21.845 14.460 69.775 15.660 ;
        RECT 21.845 15.660 25.625 15.870 ;
        RECT 68.575 15.660 69.775 15.870 ;
        RECT 9.945 15.870 39.725 17.760 ;
        RECT 47.985 16.470 51.765 17.760 ;
        RECT 9.945 17.760 51.765 18.960 ;
        RECT 47.985 18.960 51.765 20.250 ;
        RECT 9.945 18.960 39.725 29.550 ;
        RECT 66.385 15.870 96.165 29.550 ;
      LAYER Metal1 ;
        RECT 0.000 6.870 1.300 6.880 ;
        RECT -0.160 6.880 1.300 7.690 ;
        RECT 0.225 7.690 0.915 12.020 ;
        RECT 0.170 12.020 0.970 12.820 ;
        RECT 5.160 6.870 6.460 6.880 ;
        RECT 5.000 6.880 6.460 7.690 ;
        RECT 5.385 7.690 6.075 12.020 ;
        RECT 5.330 12.020 6.130 12.820 ;
        RECT 35.720 6.870 37.020 6.880 ;
        RECT 35.560 6.880 37.020 7.690 ;
        RECT 35.945 7.690 36.635 12.020 ;
        RECT 35.890 12.020 36.690 12.820 ;
        RECT 55.080 6.870 56.380 6.880 ;
        RECT 54.920 6.880 56.380 7.690 ;
        RECT 55.305 7.690 55.995 12.020 ;
        RECT 55.250 12.020 56.050 12.820 ;
        RECT 57.490 1.650 58.310 4.150 ;
        RECT 57.490 4.150 58.340 6.870 ;
        RECT 56.420 6.870 58.340 7.690 ;
        RECT 57.650 7.690 58.340 12.020 ;
        RECT 56.805 7.690 57.495 12.680 ;
        RECT 57.595 12.020 58.395 12.820 ;
        RECT 56.750 12.680 57.550 13.480 ;
        RECT 2.410 1.650 3.230 4.150 ;
        RECT 2.410 4.150 3.260 6.870 ;
        RECT 1.340 6.870 3.260 7.690 ;
        RECT 1.725 7.690 2.415 12.680 ;
        RECT 1.670 12.680 2.470 13.480 ;
        RECT 2.570 7.690 3.260 14.000 ;
        RECT 2.515 14.000 3.315 14.800 ;
        RECT 7.570 1.650 8.390 4.150 ;
        RECT 7.570 4.150 8.420 6.870 ;
        RECT 6.500 6.870 8.420 7.690 ;
        RECT 6.885 7.690 7.575 12.680 ;
        RECT 6.830 12.680 7.630 13.480 ;
        RECT 7.730 7.690 8.420 14.000 ;
        RECT 7.675 14.000 8.475 14.800 ;
        RECT 40.940 6.870 42.240 6.880 ;
        RECT 40.780 6.880 42.240 7.690 ;
        RECT 41.165 7.690 41.855 14.660 ;
        RECT 41.110 14.660 41.910 15.460 ;
        RECT 62.650 1.650 63.470 2.150 ;
        RECT 62.650 2.150 63.500 2.870 ;
        RECT 61.580 2.870 63.500 3.690 ;
        RECT 62.810 3.690 63.500 13.340 ;
        RECT 62.755 13.340 63.555 14.140 ;
        RECT 61.965 3.690 62.655 16.640 ;
        RECT 61.910 16.640 62.710 17.440 ;
        RECT 67.810 1.650 68.630 2.150 ;
        RECT 67.810 2.150 68.660 2.870 ;
        RECT 66.740 2.870 68.660 3.690 ;
        RECT 67.125 3.690 67.815 16.640 ;
        RECT 67.970 3.690 68.660 16.640 ;
        RECT 67.070 16.640 67.870 17.440 ;
        RECT 67.915 16.640 68.715 17.440 ;
        RECT 27.810 1.650 28.630 2.650 ;
        RECT 29.310 1.650 30.130 2.650 ;
        RECT 27.780 2.650 28.630 3.870 ;
        RECT 29.310 2.650 30.160 3.870 ;
        RECT 27.780 3.870 30.160 4.690 ;
        RECT 28.625 4.690 29.315 14.000 ;
        RECT 28.570 14.000 29.370 14.800 ;
        RECT 27.780 4.690 28.470 15.980 ;
        RECT 27.725 15.980 28.525 16.780 ;
        RECT 29.470 4.690 30.160 19.280 ;
        RECT 29.415 19.280 30.215 20.080 ;
        RECT 38.130 1.650 38.950 4.150 ;
        RECT 38.130 4.150 38.980 6.870 ;
        RECT 37.060 6.870 38.980 7.690 ;
        RECT 37.445 7.690 38.135 12.680 ;
        RECT 37.390 12.680 38.190 13.480 ;
        RECT 38.290 7.690 38.980 19.280 ;
        RECT 38.235 19.280 39.035 20.080 ;
        RECT 4.390 24.010 5.250 25.370 ;
        RECT 81.760 24.010 82.620 27.620 ;
        RECT 4.390 26.260 5.250 29.870 ;
        RECT 81.760 28.510 82.620 32.120 ;
        RECT 4.390 30.760 5.250 34.370 ;
        RECT 81.760 33.010 82.620 34.370 ;
        RECT 0.370 13.340 1.170 14.140 ;
        RECT 0.425 14.140 1.115 35.360 ;
        RECT 0.040 35.360 1.500 36.170 ;
        RECT 0.200 36.170 1.500 36.180 ;
        RECT 5.930 13.340 6.730 14.140 ;
        RECT 5.985 14.140 6.675 35.360 ;
        RECT 5.600 35.360 7.060 36.170 ;
        RECT 5.760 36.170 7.060 36.180 ;
        RECT 45.010 1.650 45.830 4.150 ;
        RECT 43.430 1.650 44.250 6.870 ;
        RECT 45.010 4.150 45.860 6.870 ;
        RECT 42.280 6.870 45.860 7.110 ;
        RECT 42.280 7.110 43.740 7.460 ;
        RECT 43.940 7.110 45.860 7.460 ;
        RECT 42.280 7.460 45.860 7.690 ;
        RECT 43.440 7.690 44.240 8.260 ;
        RECT 42.665 7.690 43.355 12.680 ;
        RECT 42.610 12.680 43.410 13.480 ;
        RECT 44.325 7.690 45.015 14.000 ;
        RECT 45.170 7.690 45.860 14.000 ;
        RECT 43.495 8.260 44.185 14.660 ;
        RECT 44.270 14.000 45.070 14.800 ;
        RECT 45.115 14.000 45.915 14.800 ;
        RECT 43.440 14.660 44.240 15.320 ;
        RECT 43.440 15.320 44.830 15.460 ;
        RECT 44.030 15.460 44.830 16.120 ;
        RECT 44.085 16.120 44.775 35.360 ;
        RECT 43.700 35.360 45.160 36.170 ;
        RECT 43.860 36.170 45.160 36.180 ;
        RECT 52.330 1.650 53.150 2.150 ;
        RECT 52.330 2.150 53.180 2.870 ;
        RECT 51.420 2.870 53.180 2.880 ;
        RECT 51.260 2.880 53.180 3.690 ;
        RECT 51.645 3.690 52.335 12.680 ;
        RECT 52.490 3.690 53.180 12.680 ;
        RECT 51.590 12.680 52.390 13.340 ;
        RECT 51.250 13.340 52.390 13.480 ;
        RECT 52.435 12.680 53.235 13.480 ;
        RECT 51.250 13.480 52.050 14.140 ;
        RECT 51.305 14.140 51.995 35.360 ;
        RECT 50.920 35.360 52.380 36.170 ;
        RECT 51.080 36.170 52.380 36.180 ;
        RECT 73.050 13.340 73.850 14.140 ;
        RECT 73.105 14.140 73.795 35.360 ;
        RECT 72.720 35.360 74.180 36.170 ;
        RECT 72.880 36.170 74.180 36.180 ;
        RECT 78.610 13.340 79.410 14.140 ;
        RECT 78.665 14.140 79.355 35.360 ;
        RECT 78.280 35.360 79.740 36.170 ;
        RECT 78.440 36.170 79.740 36.180 ;
        RECT 88.230 13.340 89.030 14.140 ;
        RECT 88.285 14.140 88.975 35.360 ;
        RECT 87.900 35.360 89.360 36.170 ;
        RECT 88.060 36.170 89.360 36.180 ;
        RECT 1.870 16.640 2.670 17.440 ;
        RECT 2.715 19.280 3.515 20.080 ;
        RECT 2.770 20.080 3.460 24.010 ;
        RECT 2.770 24.010 4.160 25.370 ;
        RECT 2.770 25.370 3.460 26.260 ;
        RECT 2.770 26.260 4.160 27.620 ;
        RECT 2.770 27.620 3.460 28.510 ;
        RECT 2.770 28.510 4.160 29.870 ;
        RECT 2.770 29.870 3.460 30.760 ;
        RECT 2.770 30.760 4.160 32.120 ;
        RECT 2.770 32.120 3.460 33.010 ;
        RECT 2.770 33.010 4.160 34.370 ;
        RECT 1.925 17.440 2.615 35.360 ;
        RECT 2.770 34.370 3.460 35.360 ;
        RECT 1.540 35.360 3.460 36.180 ;
        RECT 2.610 36.180 3.460 41.400 ;
        RECT 2.610 41.400 3.430 46.400 ;
        RECT 7.430 16.640 8.230 17.440 ;
        RECT 8.275 19.280 9.075 20.080 ;
        RECT 7.485 17.440 8.175 35.360 ;
        RECT 8.330 20.080 9.020 35.360 ;
        RECT 7.100 35.360 9.020 36.180 ;
        RECT 8.170 36.180 9.020 41.400 ;
        RECT 8.170 41.400 8.990 46.400 ;
        RECT 9.730 1.650 10.550 5.400 ;
        RECT 11.230 1.650 12.050 5.400 ;
        RECT 9.700 5.400 10.550 9.370 ;
        RECT 11.230 5.400 12.080 9.370 ;
        RECT 9.700 9.370 12.080 10.190 ;
        RECT 9.700 10.190 10.390 14.000 ;
        RECT 9.645 14.000 10.445 14.800 ;
        RECT 12.335 14.660 13.135 15.460 ;
        RECT 11.390 10.190 12.080 17.960 ;
        RECT 10.545 10.190 11.235 18.620 ;
        RECT 11.335 17.960 12.135 18.620 ;
        RECT 11.335 18.620 12.290 18.760 ;
        RECT 10.490 18.620 11.290 19.280 ;
        RECT 10.490 19.280 11.445 19.420 ;
        RECT 11.490 18.760 12.290 19.420 ;
        RECT 10.645 19.420 11.445 20.080 ;
        RECT 10.700 20.080 11.390 44.810 ;
        RECT 11.545 19.420 12.235 44.810 ;
        RECT 12.390 15.460 13.080 44.810 ;
        RECT 10.700 44.810 13.080 45.630 ;
        RECT 10.700 45.630 11.550 46.125 ;
        RECT 12.230 45.630 13.080 46.125 ;
        RECT 10.730 46.125 11.550 46.400 ;
        RECT 12.230 46.125 13.050 46.400 ;
        RECT 13.390 1.650 14.210 5.900 ;
        RECT 14.890 1.650 15.710 5.900 ;
        RECT 13.360 5.900 14.210 10.370 ;
        RECT 14.890 5.900 15.740 10.370 ;
        RECT 13.360 10.370 15.740 11.190 ;
        RECT 13.360 11.190 14.050 14.000 ;
        RECT 13.305 14.000 14.105 14.800 ;
        RECT 16.395 14.000 17.195 14.800 ;
        RECT 15.050 11.190 15.740 15.320 ;
        RECT 14.205 11.190 14.895 15.980 ;
        RECT 14.995 15.320 15.795 15.980 ;
        RECT 14.995 15.980 16.350 16.120 ;
        RECT 14.150 15.980 14.950 16.780 ;
        RECT 15.550 16.120 16.350 16.780 ;
        RECT 14.705 19.280 15.505 20.080 ;
        RECT 14.760 20.080 15.450 44.860 ;
        RECT 15.605 16.780 16.295 44.860 ;
        RECT 16.450 14.800 17.140 44.860 ;
        RECT 14.760 44.860 17.140 45.680 ;
        RECT 14.760 45.680 15.610 46.150 ;
        RECT 16.290 45.680 17.140 46.150 ;
        RECT 14.790 46.150 15.610 46.400 ;
        RECT 16.290 46.150 17.110 46.400 ;
        RECT 20.270 1.650 21.090 2.900 ;
        RECT 18.690 1.650 19.510 4.370 ;
        RECT 20.270 2.900 21.120 4.370 ;
        RECT 17.700 4.370 21.120 4.380 ;
        RECT 17.540 4.380 21.120 4.610 ;
        RECT 17.540 4.610 19.000 4.960 ;
        RECT 19.200 4.610 21.120 4.960 ;
        RECT 17.540 4.960 21.120 5.190 ;
        RECT 18.700 5.190 19.500 5.760 ;
        RECT 19.585 5.190 20.275 12.680 ;
        RECT 19.530 12.680 20.330 13.480 ;
        RECT 18.755 5.760 19.445 14.000 ;
        RECT 18.700 14.000 19.500 14.800 ;
        RECT 17.925 5.190 18.615 15.980 ;
        RECT 20.430 5.190 21.120 15.980 ;
        RECT 18.765 15.320 19.565 16.120 ;
        RECT 20.375 15.980 21.175 16.640 ;
        RECT 17.870 15.980 18.670 16.780 ;
        RECT 19.610 16.640 21.175 16.780 ;
        RECT 19.610 16.780 20.410 17.440 ;
        RECT 20.455 19.280 21.255 20.080 ;
        RECT 18.820 16.120 19.510 35.360 ;
        RECT 19.665 17.440 20.355 35.360 ;
        RECT 20.510 20.080 21.200 35.360 ;
        RECT 18.820 35.360 21.200 36.180 ;
        RECT 18.820 36.180 19.670 41.400 ;
        RECT 20.350 36.180 21.200 41.400 ;
        RECT 18.850 41.400 19.670 46.400 ;
        RECT 20.350 41.400 21.170 46.400 ;
        RECT 25.650 1.650 26.470 2.900 ;
        RECT 24.070 1.650 24.890 4.370 ;
        RECT 25.650 2.900 26.500 4.370 ;
        RECT 23.080 4.370 26.500 4.380 ;
        RECT 22.920 4.380 26.500 4.610 ;
        RECT 22.920 4.610 24.380 4.960 ;
        RECT 24.580 4.610 26.500 4.960 ;
        RECT 22.920 4.960 26.500 5.190 ;
        RECT 24.080 5.190 24.880 5.760 ;
        RECT 24.965 5.190 25.655 12.680 ;
        RECT 24.910 12.680 25.710 13.480 ;
        RECT 24.135 5.760 24.825 14.660 ;
        RECT 24.080 14.660 24.880 15.460 ;
        RECT 23.305 5.190 23.995 15.980 ;
        RECT 23.250 15.980 24.050 16.640 ;
        RECT 23.250 16.640 24.470 16.780 ;
        RECT 23.670 16.780 24.470 17.440 ;
        RECT 24.515 17.300 25.315 18.100 ;
        RECT 25.810 5.190 26.500 18.620 ;
        RECT 22.825 17.960 23.625 18.760 ;
        RECT 25.755 18.620 26.555 19.420 ;
        RECT 22.880 18.760 23.570 35.360 ;
        RECT 23.725 17.440 24.415 35.360 ;
        RECT 24.570 18.100 25.260 35.360 ;
        RECT 22.880 35.360 25.260 36.180 ;
        RECT 22.880 36.180 23.730 41.400 ;
        RECT 24.410 36.180 25.260 41.400 ;
        RECT 22.910 41.400 23.730 46.400 ;
        RECT 24.410 41.400 25.230 46.400 ;
        RECT 28.575 15.320 29.375 16.120 ;
        RECT 27.730 19.280 28.530 20.080 ;
        RECT 27.785 20.080 28.475 40.360 ;
        RECT 28.630 16.120 29.320 40.360 ;
        RECT 27.400 40.360 29.320 41.170 ;
        RECT 27.560 41.170 29.320 41.180 ;
        RECT 28.470 41.180 29.320 43.900 ;
        RECT 28.470 43.900 29.290 46.400 ;
        RECT 31.470 1.650 32.290 2.650 ;
        RECT 32.970 1.650 33.790 2.650 ;
        RECT 31.440 2.650 32.290 3.870 ;
        RECT 32.970 2.650 33.820 3.870 ;
        RECT 31.440 3.870 33.820 4.690 ;
        RECT 32.285 4.690 32.975 14.000 ;
        RECT 32.230 14.000 33.030 14.800 ;
        RECT 33.130 4.690 33.820 17.300 ;
        RECT 33.075 17.300 33.875 17.960 ;
        RECT 32.635 17.960 33.875 18.100 ;
        RECT 31.440 4.690 32.130 18.620 ;
        RECT 32.635 18.100 33.435 18.760 ;
        RECT 31.385 18.620 32.185 19.280 ;
        RECT 31.385 19.280 32.590 19.420 ;
        RECT 31.790 19.420 32.590 20.080 ;
        RECT 31.845 20.080 32.535 40.360 ;
        RECT 32.690 18.760 33.380 40.360 ;
        RECT 31.460 40.360 33.380 41.170 ;
        RECT 31.620 41.170 33.380 41.180 ;
        RECT 32.530 41.180 33.380 43.900 ;
        RECT 32.530 43.900 33.350 46.400 ;
        RECT 36.695 15.980 37.495 16.780 ;
        RECT 35.005 19.280 35.805 20.080 ;
        RECT 35.850 19.280 36.650 20.080 ;
        RECT 35.060 20.080 35.750 41.360 ;
        RECT 35.905 20.080 36.595 41.360 ;
        RECT 36.750 16.780 37.440 41.360 ;
        RECT 35.060 41.360 37.440 42.180 ;
        RECT 35.060 42.180 35.910 44.400 ;
        RECT 36.590 42.180 37.440 44.400 ;
        RECT 35.090 44.400 35.910 46.400 ;
        RECT 36.590 44.400 37.410 46.400 ;
        RECT 39.065 17.300 39.865 18.100 ;
        RECT 40.755 18.620 41.555 19.420 ;
        RECT 39.910 19.280 40.710 20.080 ;
        RECT 39.120 18.100 39.810 41.360 ;
        RECT 39.965 20.080 40.655 41.360 ;
        RECT 40.810 19.420 41.500 41.360 ;
        RECT 39.120 41.360 41.500 42.180 ;
        RECT 39.120 42.180 39.970 44.400 ;
        RECT 40.650 42.180 41.500 44.400 ;
        RECT 39.150 44.400 39.970 46.400 ;
        RECT 40.650 44.400 41.470 46.400 ;
        RECT 48.670 1.650 49.490 2.150 ;
        RECT 48.670 2.150 49.520 2.870 ;
        RECT 47.760 2.870 49.520 2.880 ;
        RECT 47.600 2.880 49.520 3.690 ;
        RECT 46.360 15.320 47.160 16.120 ;
        RECT 45.530 16.640 46.330 17.440 ;
        RECT 48.830 3.690 49.520 17.960 ;
        RECT 47.985 3.690 48.675 18.620 ;
        RECT 48.775 17.960 49.575 18.760 ;
        RECT 47.930 18.620 48.730 19.280 ;
        RECT 47.190 19.280 48.835 19.420 ;
        RECT 47.190 19.420 47.990 20.080 ;
        RECT 48.035 19.420 48.835 20.080 ;
        RECT 46.415 16.120 47.105 34.790 ;
        RECT 45.585 17.440 46.275 35.360 ;
        RECT 46.360 34.790 47.160 35.360 ;
        RECT 47.245 20.080 47.935 35.360 ;
        RECT 48.090 20.080 48.780 35.360 ;
        RECT 45.200 35.360 48.780 35.590 ;
        RECT 45.200 35.590 46.660 35.940 ;
        RECT 46.860 35.590 48.780 35.940 ;
        RECT 45.200 35.940 48.780 36.180 ;
        RECT 47.930 36.180 48.780 41.400 ;
        RECT 46.350 36.180 47.170 46.400 ;
        RECT 47.930 41.400 48.750 46.400 ;
        RECT 53.595 14.000 54.395 14.800 ;
        RECT 52.750 16.640 53.550 17.440 ;
        RECT 52.805 17.440 53.495 35.360 ;
        RECT 53.650 14.800 54.340 35.360 ;
        RECT 52.420 35.360 54.340 36.180 ;
        RECT 53.490 36.180 54.340 41.400 ;
        RECT 53.490 41.400 54.310 46.400 ;
        RECT 56.810 17.300 57.610 18.100 ;
        RECT 57.655 17.960 58.455 18.760 ;
        RECT 56.865 18.100 57.555 44.360 ;
        RECT 57.710 18.760 58.400 44.360 ;
        RECT 56.480 44.360 58.400 45.170 ;
        RECT 56.640 45.170 58.400 45.180 ;
        RECT 57.550 45.180 58.400 45.900 ;
        RECT 57.550 45.900 58.370 46.400 ;
        RECT 60.240 2.870 61.540 2.880 ;
        RECT 60.080 2.880 61.540 3.690 ;
        RECT 60.465 3.690 61.155 16.640 ;
        RECT 60.410 16.640 61.210 17.300 ;
        RECT 60.410 17.300 61.670 17.440 ;
        RECT 60.870 17.440 61.670 18.100 ;
        RECT 61.715 17.960 62.515 18.760 ;
        RECT 60.925 18.100 61.615 44.360 ;
        RECT 61.770 18.760 62.460 44.360 ;
        RECT 60.540 44.360 62.460 45.170 ;
        RECT 60.700 45.170 62.460 45.180 ;
        RECT 61.610 45.180 62.460 45.900 ;
        RECT 61.610 45.900 62.430 46.400 ;
        RECT 65.400 2.870 66.700 2.880 ;
        RECT 65.240 2.880 66.700 3.690 ;
        RECT 65.625 3.690 66.315 16.640 ;
        RECT 65.570 16.640 66.370 17.300 ;
        RECT 64.930 17.300 66.370 17.440 ;
        RECT 64.930 17.440 65.730 18.100 ;
        RECT 65.775 17.960 66.575 18.760 ;
        RECT 64.985 18.100 65.675 44.360 ;
        RECT 65.830 18.760 66.520 44.360 ;
        RECT 64.600 44.360 66.520 45.170 ;
        RECT 64.760 45.170 66.520 45.180 ;
        RECT 65.670 45.180 66.520 45.900 ;
        RECT 65.670 45.900 66.490 46.400 ;
        RECT 68.990 17.300 69.790 18.100 ;
        RECT 69.835 17.960 70.635 18.760 ;
        RECT 69.045 18.100 69.735 44.360 ;
        RECT 69.890 18.760 70.580 44.360 ;
        RECT 68.660 44.360 70.580 45.170 ;
        RECT 68.820 45.170 70.580 45.180 ;
        RECT 69.730 45.180 70.580 45.900 ;
        RECT 69.730 45.900 70.550 46.400 ;
        RECT 75.395 12.680 76.195 13.480 ;
        RECT 74.550 16.640 75.350 17.440 ;
        RECT 74.605 17.440 75.295 35.360 ;
        RECT 75.450 13.480 76.140 35.360 ;
        RECT 74.220 35.360 76.140 36.180 ;
        RECT 75.290 36.180 76.140 41.400 ;
        RECT 75.290 41.400 76.110 46.400 ;
        RECT 80.955 12.020 81.755 12.820 ;
        RECT 80.110 16.640 80.910 17.440 ;
        RECT 80.165 17.440 80.855 35.360 ;
        RECT 81.010 12.820 81.700 35.360 ;
        RECT 79.780 35.360 81.700 36.180 ;
        RECT 80.850 36.180 81.700 41.400 ;
        RECT 80.850 41.400 81.670 46.400 ;
        RECT 84.170 16.640 84.970 17.440 ;
        RECT 85.015 16.640 85.815 17.440 ;
        RECT 84.225 17.440 84.915 43.360 ;
        RECT 85.070 17.440 85.760 43.360 ;
        RECT 83.840 43.360 85.760 44.170 ;
        RECT 84.000 44.170 85.760 44.180 ;
        RECT 84.910 44.180 85.760 45.400 ;
        RECT 84.910 45.400 85.730 46.400 ;
        RECT 90.575 13.340 91.375 14.140 ;
        RECT 89.730 16.640 90.530 17.440 ;
        RECT 89.785 17.440 90.475 35.360 ;
        RECT 90.630 14.140 91.320 35.360 ;
        RECT 89.400 35.360 91.320 36.180 ;
        RECT 90.470 36.180 91.320 41.400 ;
        RECT 90.470 41.400 91.290 46.400 ;
      LAYER Metal2 ;
        RECT -0.110 11.740 1.250 11.790 ;
        RECT 5.050 11.740 6.410 11.790 ;
        RECT 35.610 11.740 36.970 11.790 ;
        RECT 54.970 11.740 56.330 11.790 ;
        RECT 57.315 11.740 58.675 11.790 ;
        RECT 80.675 11.740 82.035 11.790 ;
        RECT -0.110 11.790 82.035 13.050 ;
        RECT -0.110 13.050 1.250 13.060 ;
        RECT 1.390 13.050 76.475 13.060 ;
        RECT -0.110 13.060 76.475 13.100 ;
        RECT 80.675 13.050 82.035 13.100 ;
        RECT 0.090 13.100 76.475 13.110 ;
        RECT 78.330 13.060 79.690 13.110 ;
        RECT 87.950 13.060 89.310 13.110 ;
        RECT 90.295 13.060 91.655 13.110 ;
        RECT 0.090 13.110 91.655 14.370 ;
        RECT 23.045 14.370 24.425 14.380 ;
        RECT 0.090 14.370 1.450 14.420 ;
        RECT 62.475 14.370 63.835 14.420 ;
        RECT 72.770 14.370 74.130 14.420 ;
        RECT 78.330 14.370 79.690 14.420 ;
        RECT 87.950 14.370 89.310 14.420 ;
        RECT 90.295 14.370 91.655 14.420 ;
        RECT 2.235 14.370 14.385 14.430 ;
        RECT 15.960 14.370 19.940 14.430 ;
        RECT 23.045 14.380 25.160 14.430 ;
        RECT 2.235 14.430 25.160 15.030 ;
        RECT 28.290 14.370 54.675 15.030 ;
        RECT 28.290 15.030 29.650 15.040 ;
        RECT 40.685 15.030 46.195 15.040 ;
        RECT 2.235 15.030 3.595 15.080 ;
        RECT 7.395 15.030 8.755 15.080 ;
        RECT 9.365 15.030 10.725 15.080 ;
        RECT 28.290 15.040 29.655 15.080 ;
        RECT 31.950 15.030 33.310 15.080 ;
        RECT 53.315 15.030 54.675 15.080 ;
        RECT 40.685 15.040 47.440 15.080 ;
        RECT 12.055 15.030 25.160 15.090 ;
        RECT 28.295 15.080 29.655 15.090 ;
        RECT 40.685 15.080 45.110 15.090 ;
        RECT 46.080 15.080 47.440 15.090 ;
        RECT 40.685 15.090 47.585 15.690 ;
        RECT 12.055 15.090 29.655 15.740 ;
        RECT 40.830 15.690 42.190 15.740 ;
        RECT 43.160 15.690 47.585 15.740 ;
        RECT 13.060 15.740 29.655 15.750 ;
        RECT 36.415 15.700 37.775 15.750 ;
        RECT 43.605 15.740 47.585 16.350 ;
        RECT 46.080 16.350 47.440 16.360 ;
        RECT 43.750 16.350 45.110 16.400 ;
        RECT 45.250 16.360 47.440 16.400 ;
        RECT 1.590 16.360 2.950 16.410 ;
        RECT 7.150 16.360 8.510 16.410 ;
        RECT 11.760 15.750 37.775 16.410 ;
        RECT 45.250 16.400 46.610 16.410 ;
        RECT 52.470 16.360 53.830 16.410 ;
        RECT 60.130 16.360 61.490 16.410 ;
        RECT 61.630 16.360 62.990 16.410 ;
        RECT 65.290 16.360 66.650 16.410 ;
        RECT 66.790 16.360 68.995 16.410 ;
        RECT 74.270 16.360 75.630 16.410 ;
        RECT 79.830 16.360 81.190 16.410 ;
        RECT 83.890 16.360 86.095 16.410 ;
        RECT 89.450 16.360 90.810 16.410 ;
        RECT 1.590 16.410 90.810 17.670 ;
        RECT 11.745 17.670 13.125 17.680 ;
        RECT 23.390 17.670 70.070 17.680 ;
        RECT 1.590 17.670 2.950 17.720 ;
        RECT 7.150 17.670 8.510 17.720 ;
        RECT 19.330 17.670 20.690 17.720 ;
        RECT 74.270 17.670 75.630 17.720 ;
        RECT 79.830 17.670 81.190 17.720 ;
        RECT 83.890 17.670 86.095 17.720 ;
        RECT 89.450 17.670 90.810 17.720 ;
        RECT 22.545 17.680 70.915 17.720 ;
        RECT 11.055 17.680 13.125 17.730 ;
        RECT 22.545 17.720 23.905 17.730 ;
        RECT 24.235 17.720 70.915 17.730 ;
        RECT 11.055 17.730 70.915 18.330 ;
        RECT 8.600 18.330 10.880 18.340 ;
        RECT 11.055 18.330 34.155 18.340 ;
        RECT 48.495 18.330 70.915 18.340 ;
        RECT 8.600 18.340 34.155 18.380 ;
        RECT 38.785 18.330 40.145 18.380 ;
        RECT 8.600 18.380 33.715 18.390 ;
        RECT 40.475 18.340 41.835 18.390 ;
        RECT 47.650 18.340 70.915 18.390 ;
        RECT 7.900 18.390 70.915 18.990 ;
        RECT 7.900 18.990 14.880 19.000 ;
        RECT 22.545 18.990 23.905 19.040 ;
        RECT 57.375 18.990 58.735 19.040 ;
        RECT 61.435 18.990 62.795 19.040 ;
        RECT 65.495 18.990 66.855 19.040 ;
        RECT 68.185 18.990 70.915 19.040 ;
        RECT 25.475 18.990 50.565 19.040 ;
        RECT 2.435 19.000 3.795 19.050 ;
        RECT 7.900 19.000 15.785 19.050 ;
        RECT 20.175 19.000 21.535 19.050 ;
        RECT 25.475 19.040 49.115 19.050 ;
        RECT 49.185 19.040 50.565 19.050 ;
        RECT 53.885 18.990 55.265 19.050 ;
        RECT 58.985 18.990 60.365 19.050 ;
        RECT 63.385 18.990 64.765 19.050 ;
        RECT 68.185 19.040 69.565 19.050 ;
        RECT 2.435 19.050 15.785 20.310 ;
        RECT 20.175 19.050 49.115 20.310 ;
        RECT 2.435 20.310 3.795 20.360 ;
        RECT 7.995 20.310 9.355 20.360 ;
        RECT 10.365 20.310 11.725 20.360 ;
        RECT 14.425 20.310 15.785 20.360 ;
        RECT 20.175 20.310 21.535 20.360 ;
        RECT 27.450 20.310 28.810 20.360 ;
        RECT 29.135 20.310 30.495 20.360 ;
        RECT 31.510 20.310 32.870 20.360 ;
        RECT 34.725 20.310 36.930 20.360 ;
        RECT 37.955 20.310 39.315 20.360 ;
        RECT 39.630 20.310 40.990 20.360 ;
        RECT 46.910 20.310 49.115 20.360 ;
        RECT 4.130 23.750 5.510 25.130 ;
        RECT 46.080 34.510 47.440 41.850 ;
        RECT 81.500 32.750 82.880 34.130 ;
        RECT 46.850 46.910 48.230 48.290 ;
        RECT 48.850 46.910 50.230 48.290 ;
        RECT 50.850 46.910 52.230 48.290 ;
        RECT 52.850 46.910 54.230 48.290 ;
        RECT 54.850 46.910 56.230 48.290 ;
        RECT 56.850 46.910 58.230 48.290 ;
        RECT 58.850 46.910 60.230 48.290 ;
        RECT 60.850 46.910 62.230 48.290 ;
        RECT 62.850 46.910 64.230 48.290 ;
        RECT 64.850 46.910 66.230 48.290 ;
        RECT 66.850 46.910 68.230 48.290 ;
        RECT 68.850 46.910 70.230 48.290 ;
        RECT 70.850 46.910 72.230 48.290 ;
        RECT 72.850 46.910 74.230 48.290 ;
        RECT 74.850 46.910 76.230 48.290 ;
        RECT 76.850 46.910 78.230 48.290 ;
        RECT 78.850 46.910 80.230 48.290 ;
        RECT 80.850 46.910 82.230 48.290 ;
        RECT 82.850 46.910 84.230 48.290 ;
        RECT 84.850 46.910 86.230 48.290 ;
        RECT 86.850 46.910 88.230 48.290 ;
        RECT 88.850 46.910 90.230 48.290 ;
        RECT 90.850 46.910 92.230 48.290 ;
        RECT 92.850 46.910 94.230 48.290 ;
        RECT -1.150 46.910 0.230 48.290 ;
        RECT 0.850 46.910 2.230 48.290 ;
        RECT 2.850 46.910 4.230 48.290 ;
        RECT 4.850 46.910 6.230 48.290 ;
        RECT 6.850 46.910 8.230 48.290 ;
        RECT 8.850 46.910 10.230 48.290 ;
        RECT 10.850 46.910 12.230 48.290 ;
        RECT 12.850 46.910 14.230 48.290 ;
        RECT 14.850 46.910 16.230 48.290 ;
        RECT 16.850 46.910 18.230 48.290 ;
        RECT 18.850 46.910 20.230 48.290 ;
        RECT 20.850 46.910 22.230 48.290 ;
        RECT 22.850 46.910 24.230 48.290 ;
        RECT 24.850 46.910 26.230 48.290 ;
        RECT 26.850 46.910 28.230 48.290 ;
        RECT 28.850 46.910 30.230 48.290 ;
        RECT 30.850 46.910 32.230 48.290 ;
        RECT 32.850 46.910 34.230 48.290 ;
        RECT 34.850 46.910 36.230 48.290 ;
        RECT 36.850 46.910 38.230 48.290 ;
        RECT 38.850 46.910 40.230 48.290 ;
        RECT 40.850 46.910 42.230 48.290 ;
        RECT 42.850 46.910 44.230 48.290 ;
        RECT 44.850 46.910 46.230 48.290 ;
        RECT 23.800 2.450 25.160 6.040 ;
        RECT 43.160 3.700 44.520 8.540 ;
        RECT -1.150 -0.240 0.230 1.140 ;
        RECT 0.850 -0.240 2.230 1.140 ;
        RECT 2.850 -0.240 4.230 1.140 ;
        RECT 4.850 -0.240 6.230 1.140 ;
        RECT 6.850 -0.240 8.230 1.140 ;
        RECT 8.850 -0.240 10.230 1.140 ;
        RECT 10.850 -0.240 12.230 1.140 ;
        RECT 12.850 -0.240 14.230 1.140 ;
        RECT 14.850 -0.240 16.230 1.140 ;
        RECT 16.850 -0.240 18.230 1.140 ;
        RECT 18.850 -0.240 20.230 1.140 ;
        RECT 20.850 -0.240 22.230 1.140 ;
        RECT 22.850 -0.240 24.230 1.140 ;
        RECT 24.850 -0.240 26.230 1.140 ;
        RECT 26.850 -0.240 28.230 1.140 ;
        RECT 28.850 -0.240 30.230 1.140 ;
        RECT 30.850 -0.240 32.230 1.140 ;
        RECT 32.850 -0.240 34.230 1.140 ;
        RECT 34.850 -0.240 36.230 1.140 ;
        RECT 36.850 -0.240 38.230 1.140 ;
        RECT 38.850 -0.240 40.230 1.140 ;
        RECT 40.850 -0.240 42.230 1.140 ;
        RECT 42.850 -0.240 44.230 1.140 ;
        RECT 44.850 -0.240 46.230 1.140 ;
        RECT 18.420 2.450 19.780 6.040 ;
        RECT 60.850 -0.240 62.230 1.140 ;
        RECT 62.850 -0.240 64.230 1.140 ;
        RECT 64.850 -0.240 66.230 1.140 ;
        RECT 66.850 -0.240 68.230 1.140 ;
        RECT 68.850 -0.240 70.230 1.140 ;
        RECT 70.850 -0.240 72.230 1.140 ;
        RECT 72.850 -0.240 74.230 1.140 ;
        RECT 74.850 -0.240 76.230 1.140 ;
        RECT 76.850 -0.240 78.230 1.140 ;
        RECT 78.850 -0.240 80.230 1.140 ;
        RECT 80.850 -0.240 82.230 1.140 ;
        RECT 82.850 -0.240 84.230 1.140 ;
        RECT 84.850 -0.240 86.230 1.140 ;
        RECT 86.850 -0.240 88.230 1.140 ;
        RECT 88.850 -0.240 90.230 1.140 ;
        RECT 90.850 -0.240 92.230 1.140 ;
        RECT 92.850 -0.240 94.230 1.140 ;
        RECT 46.850 -0.240 48.230 1.140 ;
        RECT 48.850 -0.240 50.230 1.140 ;
        RECT 50.850 -0.240 52.230 1.140 ;
        RECT 52.850 -0.240 54.230 1.140 ;
        RECT 54.850 -0.240 56.230 1.140 ;
        RECT 56.850 -0.240 58.230 1.140 ;
        RECT 58.850 -0.240 60.230 1.140 ;
      LAYER Metal3 ;
        RECT 23.045 14.370 24.425 15.750 ;
        RECT 11.745 17.670 13.125 19.050 ;
        RECT 24.925 17.010 26.305 18.390 ;
        RECT 4.130 23.750 5.510 23.800 ;
        RECT 24.975 18.390 26.255 23.800 ;
        RECT 4.130 23.800 26.255 25.080 ;
        RECT 4.130 25.080 5.510 25.130 ;
      LAYER Metal4 ;
        RECT 47.985 16.470 51.765 20.250 ;
        RECT 21.845 13.170 25.625 15.870 ;
        RECT 9.945 15.870 39.725 20.950 ;
        RECT 9.945 20.950 14.125 25.570 ;
        RECT 35.745 20.950 39.725 25.570 ;
        RECT 9.945 25.570 39.725 29.550 ;
        RECT 66.385 15.870 96.165 20.950 ;
        RECT 66.385 20.950 70.565 25.570 ;
        RECT 92.185 20.950 96.165 25.570 ;
        RECT 66.385 25.570 96.165 29.550 ;
      LAYER Metal5 ;
        RECT 12.135 17.760 50.475 18.960 ;
        RECT 12.135 18.960 37.735 27.560 ;
        RECT 23.135 14.460 69.775 15.660 ;
        RECT 68.575 15.660 69.775 18.960 ;
        RECT 68.575 18.960 94.175 27.560 ;
      LAYER Nwell ;
        RECT -1.260 34.690 92.160 48.050 ;
  END
END OPAM_LIN_flat
